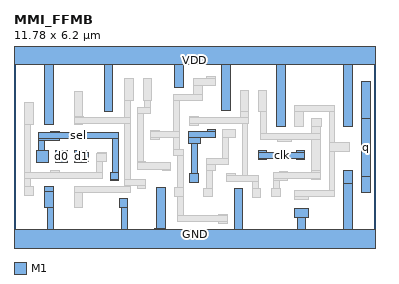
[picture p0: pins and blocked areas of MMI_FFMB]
MACRO MMI_FFMB
	CLASS CORE ;
	FOREIGN MMI_FFMB 0 0 ;
	SIZE 11.78 BY 6.2 ;
	SYMMETRY X Y ;
	SITE CORE1 ;
	PIN d0
		DIRECTION input ;
		USE SIGNAL ;
		PORT
			LAYER M1 ;
			RECT 1.36 2.6 1.74 2.98 ;
		END
		AntennaGateArea 0.3465 ;
	END d0
	PIN sel
		DIRECTION input ;
		USE SIGNAL ;
		PORT
			LAYER M1 ;
			RECT 1.2 3.575 1.48 3.59 ;
			LAYER M1 ;
			RECT 0.815 3.38 3.42 3.575 ;
			LAYER M1 ;
			RECT 0.815 3.31 1.48 3.38 ;
			LAYER M1 ;
			RECT 0.815 2.98 1.005 3.31 ;
			LAYER M1 ;
			RECT 0.735 2.6 1.11 2.98 ;
			LAYER M1 ;
			RECT 3.225 2.275 3.42 3.38 ;
			LAYER M1 ;
			RECT 3.135 2.04 3.42 2.275 ;
			LAYER M1 ;
			RECT 3.135 1.995 3.415 2.04 ;
		END
		AntennaGateArea 0.51975 ;
	END sel
	PIN GND
		DIRECTION inout ;
		USE GROUND ;
		PORT
			LAYER M1 ;
			RECT 10.75 1.925 11.03 2.325 ;
			LAYER M1 ;
			RECT 1.005 1.635 1.285 1.825 ;
			LAYER M1 ;
			RECT 1.005 1.125 1.29 1.635 ;
			LAYER M1 ;
			RECT 3.43 1.125 3.71 1.405 ;
			LAYER M1 ;
			RECT 1.1 0.42 1.29 1.125 ;
			LAYER M1 ;
			RECT 3.52 0.42 3.71 1.125 ;
			LAYER M1 ;
			RECT 4.655 0.425 4.935 1.79 ;
			LAYER M1 ;
			RECT 4.595 0.42 4.935 0.425 ;
			LAYER M1 ;
			RECT 7.185 0.42 7.465 1.76 ;
			LAYER M1 ;
			RECT 9.15 0.81 9.6 1.09 ;
			LAYER M1 ;
			RECT 9.235 0.42 9.515 0.81 ;
			LAYER M1 ;
			RECT 10.745 0.42 11.03 1.925 ;
			LAYER M1 ;
			RECT 0 -0.42 11.78 0.42 ;
		END
	END GND
	PIN q
		DIRECTION output ;
		USE SIGNAL ;
		PORT
			LAYER M1 ;
			RECT 11.34 4.04 11.62 5.225 ;
			LAYER M1 ;
			RECT 11.34 2.145 11.625 4.04 ;
			LAYER M1 ;
			RECT 11.34 1.625 11.62 2.145 ;
		END
		AntennaDiffArea 0.91245 ;
	END q
	PIN d1
		DIRECTION input ;
		USE SIGNAL ;
		PORT
			LAYER M1 ;
			RECT 1.98 2.92 2.36 2.98 ;
			LAYER M1 ;
			RECT 1.98 2.64 2.42 2.92 ;
			LAYER M1 ;
			RECT 1.98 2.6 2.36 2.64 ;
		END
		AntennaGateArea 0.3465 ;
	END d1
	PIN VDD
		DIRECTION inout ;
		USE POWER ;
		PORT
			LAYER M1 ;
			RECT 0 5.78 11.78 6.62 ;
			LAYER M1 ;
			RECT 1.005 3.845 1.285 5.78 ;
			LAYER M1 ;
			RECT 2.945 4.255 3.225 5.78 ;
			LAYER M1 ;
			RECT 5.25 5.04 5.53 5.78 ;
			LAYER M1 ;
			RECT 6.78 4.28 7.06 5.78 ;
			LAYER M1 ;
			RECT 8.565 3.755 8.845 5.78 ;
			LAYER M1 ;
			RECT 10.75 3.755 11.03 5.78 ;
		END
	END VDD
	PIN clk
		DIRECTION input ;
		USE CLOCK ;
		PORT
			LAYER M1 ;
			RECT 6.3 3.595 6.58 3.675 ;
			LAYER M1 ;
			RECT 5.705 3.4 6.58 3.595 ;
			LAYER M1 ;
			RECT 5.705 3.22 6.08 3.4 ;
			LAYER M1 ;
			RECT 6.3 3.395 6.58 3.4 ;
			LAYER M1 ;
			RECT 5.795 2.235 5.99 3.22 ;
			LAYER M1 ;
			RECT 7.975 2.91 8.255 2.97 ;
			LAYER M1 ;
			RECT 9.21 2.91 9.49 2.975 ;
			LAYER M1 ;
			RECT 7.975 2.72 9.49 2.91 ;
			LAYER M1 ;
			RECT 7.975 2.69 8.255 2.72 ;
			LAYER M1 ;
			RECT 9.21 2.695 9.49 2.72 ;
			LAYER M1 ;
			RECT 5.735 1.955 6.015 2.235 ;
		END
		AntennaGateArea 0.44625 ;
	END clk
	OBS
		LAYER M1 ;
		RECT 0.34 3.845 0.62 4.545 ;
		LAYER M1 ;
		RECT 1.97 4.08 2.25 4.91 ;
		LAYER M1 ;
		RECT 3.62 4.62 3.9 5.32 ;
		LAYER M1 ;
		RECT 4.21 4.62 4.49 5.32 ;
		LAYER M1 ;
		RECT 6.29 5.32 6.57 5.395 ;
		LAYER M1 ;
		RECT 5.855 5.115 6.57 5.32 ;
		LAYER M1 ;
		RECT 5.855 4.81 6.135 5.115 ;
		LAYER M1 ;
		RECT 5.205 4.62 6.135 4.81 ;
		LAYER M1 ;
		RECT 1.97 4.055 2.255 4.08 ;
		LAYER M1 ;
		RECT 3.62 4.055 3.81 4.62 ;
		LAYER M1 ;
		RECT 4.25 4.38 4.44 4.62 ;
		LAYER M1 ;
		RECT 1.97 3.865 3.81 4.055 ;
		LAYER M1 ;
		RECT 1.97 3.85 2.25 3.865 ;
		LAYER M1 ;
		RECT 0.345 2.28 0.535 3.845 ;
		LAYER M1 ;
		RECT 2.735 2.89 3.015 2.91 ;
		LAYER M1 ;
		RECT 2.705 2.63 3.015 2.89 ;
		LAYER M1 ;
		RECT 1.2 2.28 1.48 2.345 ;
		LAYER M1 ;
		RECT 2.705 2.28 2.895 2.63 ;
		LAYER M1 ;
		RECT 0.345 2.085 2.895 2.28 ;
		LAYER M1 ;
		RECT 0.345 1.825 0.535 2.085 ;
		LAYER M1 ;
		RECT 1.2 2.065 1.48 2.085 ;
		LAYER M1 ;
		RECT 3.62 2.04 3.81 3.865 ;
		LAYER M1 ;
		RECT 4.025 4.185 4.44 4.38 ;
		LAYER M1 ;
		RECT 4.025 2.63 4.22 4.185 ;
		LAYER M1 ;
		RECT 4.455 3.595 4.735 3.64 ;
		LAYER M1 ;
		RECT 5.205 3.595 5.395 4.62 ;
		LAYER M1 ;
		RECT 7.375 4.255 7.655 4.955 ;
		LAYER M1 ;
		RECT 7.965 4.255 8.245 4.955 ;
		LAYER M1 ;
		RECT 5.725 4.075 6.005 4.08 ;
		LAYER M1 ;
		RECT 7.375 4.075 7.645 4.255 ;
		LAYER M1 ;
		RECT 5.725 3.88 7.645 4.075 ;
		LAYER M1 ;
		RECT 5.725 3.8 6.005 3.88 ;
		LAYER M1 ;
		RECT 4.455 3.4 5.395 3.595 ;
		LAYER M1 ;
		RECT 4.455 3.36 4.735 3.4 ;
		LAYER M1 ;
		RECT 5.205 3.02 5.395 3.4 ;
		LAYER M1 ;
		RECT 6.815 3.4 7.235 3.68 ;
		LAYER M1 ;
		RECT 5.205 2.83 5.515 3.02 ;
		LAYER M1 ;
		RECT 4.02 2.595 4.3 2.63 ;
		LAYER M1 ;
		RECT 4.83 2.595 5.11 2.61 ;
		LAYER M1 ;
		RECT 4.02 2.35 5.115 2.595 ;
		LAYER M1 ;
		RECT 4.83 2.33 5.11 2.35 ;
		LAYER M1 ;
		RECT 3.62 1.85 4.3 2.04 ;
		LAYER M1 ;
		RECT 0.34 1.51 0.62 1.825 ;
		LAYER M1 ;
		RECT 1.965 1.795 2.245 1.825 ;
		LAYER M1 ;
		RECT 3.62 1.795 3.81 1.85 ;
		LAYER M1 ;
		RECT 1.965 1.605 3.81 1.795 ;
		LAYER M1 ;
		RECT 4.02 1.76 4.3 1.85 ;
		LAYER M1 ;
		RECT 5.32 1.79 5.515 2.83 ;
		LAYER M1 ;
		RECT 6.815 2.73 7.005 3.4 ;
		LAYER M1 ;
		RECT 6.27 2.535 7.005 2.73 ;
		LAYER M1 ;
		RECT 6.27 2.325 6.585 2.535 ;
		LAYER M1 ;
		RECT 1.965 1.125 2.245 1.605 ;
		LAYER M1 ;
		RECT 5.245 1.475 5.525 1.79 ;
		LAYER M1 ;
		RECT 6.27 1.755 6.465 2.325 ;
		LAYER M1 ;
		RECT 6.945 2.155 7.225 2.24 ;
		LAYER M1 ;
		RECT 7.44 2.155 7.635 3.88 ;
		LAYER M1 ;
		RECT 8.05 3.55 8.245 4.255 ;
		LAYER M1 ;
		RECT 9.155 4.26 10.47 4.455 ;
		LAYER M1 ;
		RECT 9.155 3.755 9.435 4.26 ;
		LAYER M1 ;
		RECT 9.705 4.035 9.99 4.04 ;
		LAYER M1 ;
		RECT 9.705 3.755 10.025 4.035 ;
		LAYER M1 ;
		RECT 9.705 3.55 9.99 3.755 ;
		LAYER M1 ;
		RECT 8.05 3.355 9.99 3.55 ;
		LAYER M1 ;
		RECT 8.61 3.265 9.04 3.355 ;
		LAYER M1 ;
		RECT 9.705 2.32 9.99 3.355 ;
		LAYER M1 ;
		RECT 10.28 3.24 10.47 4.26 ;
		LAYER M1 ;
		RECT 10.28 3.235 10.805 3.24 ;
		LAYER M1 ;
		RECT 10.28 2.955 10.94 3.235 ;
		LAYER M1 ;
		RECT 8.66 2.275 8.94 2.3 ;
		LAYER M1 ;
		RECT 9.705 2.275 9.995 2.32 ;
		LAYER M1 ;
		RECT 6.945 1.96 7.975 2.155 ;
		LAYER M1 ;
		RECT 7.78 1.76 7.975 1.96 ;
		LAYER M1 ;
		RECT 8.47 2.08 9.995 2.275 ;
		LAYER M1 ;
		RECT 8.47 2.02 8.94 2.08 ;
		LAYER M1 ;
		RECT 9.715 2.04 9.995 2.08 ;
		LAYER M1 ;
		RECT 8.47 1.76 8.66 2.02 ;
		LAYER M1 ;
		RECT 6.18 1.48 6.465 1.755 ;
		LAYER M1 ;
		RECT 6.18 1.475 6.46 1.48 ;
		LAYER M1 ;
		RECT 5.32 0.86 5.515 1.475 ;
		LAYER M1 ;
		RECT 6.68 0.86 6.96 0.9 ;
		LAYER M1 ;
		RECT 5.32 0.665 6.96 0.86 ;
		LAYER M1 ;
		RECT 6.68 0.62 6.96 0.665 ;
		LAYER M1 ;
		RECT 7.775 1.445 8.055 1.76 ;
		LAYER M1 ;
		RECT 8.415 1.48 8.695 1.76 ;
		LAYER M1 ;
		RECT 10.28 1.685 10.47 2.955 ;
		LAYER M1 ;
		RECT 9.38 1.68 10.47 1.685 ;
		LAYER M1 ;
		RECT 9.15 1.49 10.47 1.68 ;
		LAYER M1 ;
		RECT 9.15 1.4 9.6 1.49 ;
	END
END MMI_FFMB
